VERSION 5.8 ;
BUSBITCHARS "[]" ;
DIVIDERCHAR "/" ;
UNITS
    DATABASE MICRONS 1000 ;
END UNITS

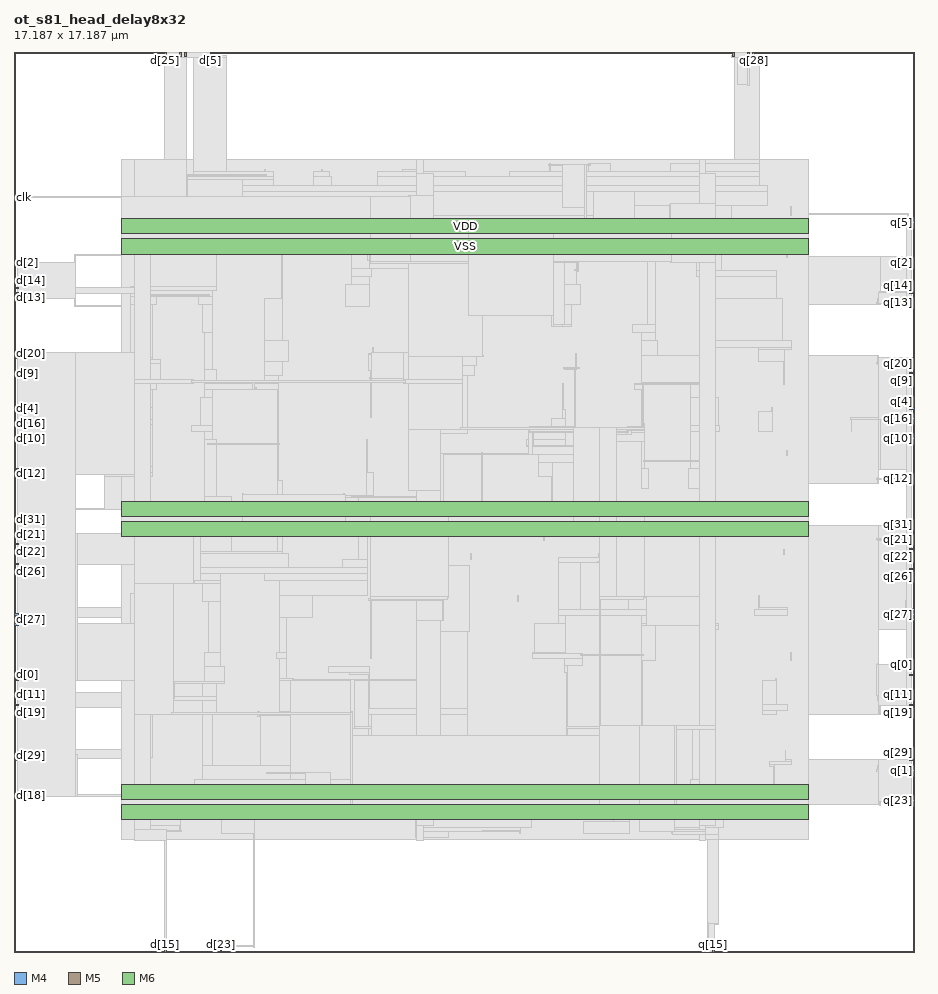
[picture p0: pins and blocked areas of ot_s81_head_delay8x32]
MACRO ot_s81_head_delay8x32
  FOREIGN ot_s81_head_delay8x32 0 0 ;
  CLASS BLOCK ;
  SIZE 17.187 BY 17.187 ;
  PIN clk
    DIRECTION INPUT ;
    USE SIGNAL ;
    PORT
      LAYER M4 ;
        RECT  0 14.4 0.084 14.424 ;
    END
  END clk
  PIN d[0]
    DIRECTION INPUT ;
    USE SIGNAL ;
    PORT
      LAYER M4 ;
        RECT  0 5.28 0.084 5.304 ;
    END
  END d[0]
  PIN d[10]
    DIRECTION INPUT ;
    USE SIGNAL ;
    PORT
      LAYER M4 ;
        RECT  0 9.792 0.084 9.816 ;
    END
  END d[10]
  PIN d[11]
    DIRECTION INPUT ;
    USE SIGNAL ;
    PORT
      LAYER M4 ;
        RECT  0 4.896 0.084 4.92 ;
    END
  END d[11]
  PIN d[12]
    DIRECTION INPUT ;
    USE SIGNAL ;
    PORT
      LAYER M4 ;
        RECT  0 9.12 0.084 9.144 ;
    END
  END d[12]
  PIN d[13]
    DIRECTION INPUT ;
    USE SIGNAL ;
    PORT
      LAYER M4 ;
        RECT  0 12.48 0.084 12.504 ;
    END
  END d[13]
  PIN d[14]
    DIRECTION INPUT ;
    USE SIGNAL ;
    PORT
      LAYER M4 ;
        RECT  0 12.672 0.084 12.696 ;
    END
  END d[14]
  PIN d[15]
    DIRECTION INPUT ;
    USE SIGNAL ;
    PORT
      LAYER M5 ;
        RECT  2.88 0 2.904 0.084 ;
    END
  END d[15]
  PIN d[16]
    DIRECTION INPUT ;
    USE SIGNAL ;
    PORT
      LAYER M4 ;
        RECT  0 10.08 0.084 10.104 ;
    END
  END d[16]
  PIN d[17]
    DIRECTION INPUT ;
    USE SIGNAL ;
    PORT
      LAYER M4 ;
        RECT  0 5.184 0.084 5.208 ;
    END
  END d[17]
  PIN d[18]
    DIRECTION INPUT ;
    USE SIGNAL ;
    PORT
      LAYER M4 ;
        RECT  0 2.976 0.084 3 ;
    END
  END d[18]
  PIN d[19]
    DIRECTION INPUT ;
    USE SIGNAL ;
    PORT
      LAYER M4 ;
        RECT  0 4.704 0.084 4.728 ;
    END
  END d[19]
  PIN d[1]
    DIRECTION INPUT ;
    USE SIGNAL ;
    PORT
      LAYER M4 ;
        RECT  0 3.648 0.084 3.672 ;
    END
  END d[1]
  PIN d[20]
    DIRECTION INPUT ;
    USE SIGNAL ;
    PORT
      LAYER M4 ;
        RECT  0 11.424 0.084 11.448 ;
    END
  END d[20]
  PIN d[21]
    DIRECTION INPUT ;
    USE SIGNAL ;
    PORT
      LAYER M4 ;
        RECT  0 7.968 0.084 7.992 ;
    END
  END d[21]
  PIN d[22]
    DIRECTION INPUT ;
    USE SIGNAL ;
    PORT
      LAYER M4 ;
        RECT  0 7.776 0.084 7.8 ;
    END
  END d[22]
  PIN d[23]
    DIRECTION INPUT ;
    USE SIGNAL ;
    PORT
      LAYER M5 ;
        RECT  3.936 0 3.96 0.084 ;
    END
  END d[23]
  PIN d[24]
    DIRECTION INPUT ;
    USE SIGNAL ;
    PORT
      LAYER M4 ;
        RECT  0 11.328 0.084 11.352 ;
    END
  END d[24]
  PIN d[25]
    DIRECTION INPUT ;
    USE SIGNAL ;
    PORT
      LAYER M5 ;
        RECT  2.88 17.103 2.904 17.187 ;
    END
  END d[25]
  PIN d[26]
    DIRECTION INPUT ;
    USE SIGNAL ;
    PORT
      LAYER M4 ;
        RECT  0 7.392 0.084 7.416 ;
    END
  END d[26]
  PIN d[27]
    DIRECTION INPUT ;
    USE SIGNAL ;
    PORT
      LAYER M4 ;
        RECT  0 6.336 0.084 6.36 ;
    END
  END d[27]
  PIN d[28]
    DIRECTION INPUT ;
    USE SIGNAL ;
    PORT
      LAYER M5 ;
        RECT  3.264 17.103 3.288 17.187 ;
    END
  END d[28]
  PIN d[29]
    DIRECTION INPUT ;
    USE SIGNAL ;
    PORT
      LAYER M4 ;
        RECT  0 3.744 0.084 3.768 ;
    END
  END d[29]
  PIN d[2]
    DIRECTION INPUT ;
    USE SIGNAL ;
    PORT
      LAYER M4 ;
        RECT  0 13.152 0.084 13.176 ;
    END
  END d[2]
  PIN d[30]
    DIRECTION INPUT ;
    USE SIGNAL ;
    PORT
      LAYER M5 ;
        RECT  3.168 17.103 3.192 17.187 ;
    END
  END d[30]
  PIN d[31]
    DIRECTION INPUT ;
    USE SIGNAL ;
    PORT
      LAYER M4 ;
        RECT  0 8.256 0.084 8.28 ;
    END
  END d[31]
  PIN d[3]
    DIRECTION INPUT ;
    USE SIGNAL ;
    PORT
      LAYER M4 ;
        RECT  0 6.432 0.084 6.456 ;
    END
  END d[3]
  PIN d[4]
    DIRECTION INPUT ;
    USE SIGNAL ;
    PORT
      LAYER M4 ;
        RECT  0 10.368 0.084 10.392 ;
    END
  END d[4]
  PIN d[5]
    DIRECTION INPUT ;
    USE SIGNAL ;
    PORT
      LAYER M5 ;
        RECT  3.744 17.103 3.768 17.187 ;
    END
  END d[5]
  PIN d[6]
    DIRECTION INPUT ;
    USE SIGNAL ;
    PORT
      LAYER M4 ;
        RECT  0 12.576 0.084 12.6 ;
    END
  END d[6]
  PIN d[7]
    DIRECTION INPUT ;
    USE SIGNAL ;
    PORT
      LAYER M4 ;
        RECT  0 9.216 0.084 9.24 ;
    END
  END d[7]
  PIN d[8]
    DIRECTION INPUT ;
    USE SIGNAL ;
    PORT
      LAYER M4 ;
        RECT  0 6.24 0.084 6.264 ;
    END
  END d[8]
  PIN d[9]
    DIRECTION INPUT ;
    USE SIGNAL ;
    PORT
      LAYER M4 ;
        RECT  0 11.04 0.084 11.064 ;
    END
  END d[9]
  PIN q[0]
    DIRECTION OUTPUT ;
    USE SIGNAL ;
    PORT
      LAYER M4 ;
        RECT  17.103 5.472 17.187 5.496 ;
    END
  END q[0]
  PIN q[10]
    DIRECTION OUTPUT ;
    USE SIGNAL ;
    PORT
      LAYER M4 ;
        RECT  17.103 9.792 17.187 9.816 ;
    END
  END q[10]
  PIN q[11]
    DIRECTION OUTPUT ;
    USE SIGNAL ;
    PORT
      LAYER M4 ;
        RECT  17.103 4.896 17.187 4.92 ;
    END
  END q[11]
  PIN q[12]
    DIRECTION OUTPUT ;
    USE SIGNAL ;
    PORT
      LAYER M4 ;
        RECT  17.103 9.024 17.187 9.048 ;
    END
  END q[12]
  PIN q[13]
    DIRECTION OUTPUT ;
    USE SIGNAL ;
    PORT
      LAYER M4 ;
        RECT  17.103 12.384 17.187 12.408 ;
    END
  END q[13]
  PIN q[14]
    DIRECTION OUTPUT ;
    USE SIGNAL ;
    PORT
      LAYER M4 ;
        RECT  17.103 12.576 17.187 12.6 ;
    END
  END q[14]
  PIN q[15]
    DIRECTION OUTPUT ;
    USE SIGNAL ;
    PORT
      LAYER M5 ;
        RECT  13.344 0 13.368 0.084 ;
    END
  END q[15]
  PIN q[16]
    DIRECTION OUTPUT ;
    USE SIGNAL ;
    PORT
      LAYER M4 ;
        RECT  17.103 10.176 17.187 10.2 ;
    END
  END q[16]
  PIN q[17]
    DIRECTION OUTPUT ;
    USE SIGNAL ;
    PORT
      LAYER M4 ;
        RECT  17.103 5.28 17.187 5.304 ;
    END
  END q[17]
  PIN q[18]
    DIRECTION OUTPUT ;
    USE SIGNAL ;
    PORT
      LAYER M5 ;
        RECT  13.248 0 13.272 0.084 ;
    END
  END q[18]
  PIN q[19]
    DIRECTION OUTPUT ;
    USE SIGNAL ;
    PORT
      LAYER M4 ;
        RECT  17.103 4.704 17.187 4.728 ;
    END
  END q[19]
  PIN q[1]
    DIRECTION OUTPUT ;
    USE SIGNAL ;
    PORT
      LAYER M4 ;
        RECT  17.103 3.456 17.187 3.48 ;
    END
  END q[1]
  PIN q[20]
    DIRECTION OUTPUT ;
    USE SIGNAL ;
    PORT
      LAYER M4 ;
        RECT  17.103 11.232 17.187 11.256 ;
    END
  END q[20]
  PIN q[21]
    DIRECTION OUTPUT ;
    USE SIGNAL ;
    PORT
      LAYER M4 ;
        RECT  17.103 7.872 17.187 7.896 ;
    END
  END q[21]
  PIN q[22]
    DIRECTION OUTPUT ;
    USE SIGNAL ;
    PORT
      LAYER M4 ;
        RECT  17.103 7.68 17.187 7.704 ;
    END
  END q[22]
  PIN q[23]
    DIRECTION OUTPUT ;
    USE SIGNAL ;
    PORT
      LAYER M4 ;
        RECT  17.103 2.88 17.187 2.904 ;
    END
  END q[23]
  PIN q[24]
    DIRECTION OUTPUT ;
    USE SIGNAL ;
    PORT
      LAYER M4 ;
        RECT  17.103 11.328 17.187 11.352 ;
    END
  END q[24]
  PIN q[25]
    DIRECTION OUTPUT ;
    USE SIGNAL ;
    PORT
      LAYER M5 ;
        RECT  13.728 17.103 13.752 17.187 ;
    END
  END q[25]
  PIN q[26]
    DIRECTION OUTPUT ;
    USE SIGNAL ;
    PORT
      LAYER M4 ;
        RECT  17.103 7.296 17.187 7.32 ;
    END
  END q[26]
  PIN q[27]
    DIRECTION OUTPUT ;
    USE SIGNAL ;
    PORT
      LAYER M4 ;
        RECT  17.103 6.432 17.187 6.456 ;
    END
  END q[27]
  PIN q[28]
    DIRECTION OUTPUT ;
    USE SIGNAL ;
    PORT
      LAYER M5 ;
        RECT  14.112 17.103 14.136 17.187 ;
    END
  END q[28]
  PIN q[29]
    DIRECTION OUTPUT ;
    USE SIGNAL ;
    PORT
      LAYER M4 ;
        RECT  17.103 3.648 17.187 3.672 ;
    END
  END q[29]
  PIN q[2]
    DIRECTION OUTPUT ;
    USE SIGNAL ;
    PORT
      LAYER M4 ;
        RECT  17.103 13.152 17.187 13.176 ;
    END
  END q[2]
  PIN q[30]
    DIRECTION OUTPUT ;
    USE SIGNAL ;
    PORT
      LAYER M5 ;
        RECT  14.016 17.103 14.04 17.187 ;
    END
  END q[30]
  PIN q[31]
    DIRECTION OUTPUT ;
    USE SIGNAL ;
    PORT
      LAYER M4 ;
        RECT  17.103 8.16 17.187 8.184 ;
    END
  END q[31]
  PIN q[3]
    DIRECTION OUTPUT ;
    USE SIGNAL ;
    PORT
      LAYER M4 ;
        RECT  17.103 6.528 17.187 6.552 ;
    END
  END q[3]
  PIN q[4]
    DIRECTION OUTPUT ;
    USE SIGNAL ;
    PORT
      LAYER M4 ;
        RECT  17.103 10.368 17.187 10.392 ;
    END
  END q[4]
  PIN q[5]
    DIRECTION OUTPUT ;
    USE SIGNAL ;
    PORT
      LAYER M4 ;
        RECT  17.103 13.92 17.187 13.944 ;
    END
  END q[5]
  PIN q[6]
    DIRECTION OUTPUT ;
    USE SIGNAL ;
    PORT
      LAYER M4 ;
        RECT  17.103 12.48 17.187 12.504 ;
    END
  END q[6]
  PIN q[7]
    DIRECTION OUTPUT ;
    USE SIGNAL ;
    PORT
      LAYER M4 ;
        RECT  17.103 9.12 17.187 9.144 ;
    END
  END q[7]
  PIN q[8]
    DIRECTION OUTPUT ;
    USE SIGNAL ;
    PORT
      LAYER M4 ;
        RECT  17.103 6.336 17.187 6.36 ;
    END
  END q[8]
  PIN q[9]
    DIRECTION OUTPUT ;
    USE SIGNAL ;
    PORT
      LAYER M4 ;
        RECT  17.103 11.04 17.187 11.064 ;
    END
  END q[9]
  PIN VDD
    DIRECTION INOUT ;
    USE POWER ;
    PORT
      LAYER M6 ;
        RECT  2.052 13.713 15.174 14.001 ;
        RECT  2.052 8.313 15.174 8.601 ;
        RECT  2.052 2.913 15.174 3.201 ;
    END
  END VDD
  PIN VSS
    DIRECTION INOUT ;
    USE GROUND ;
    PORT
      LAYER M6 ;
        RECT  2.052 13.329 15.174 13.617 ;
        RECT  2.052 7.929 15.174 8.217 ;
        RECT  2.052 2.529 15.174 2.817 ;
    END
  END VSS
  OBS
    LAYER RVTN ;
     RECT  2.052 2.16 15.174 2.295 ;
     RECT  2.052 2.565 15.174 2.835 ;
     RECT  2.052 3.105 15.174 3.375 ;
     RECT  2.052 3.645 15.174 3.915 ;
     RECT  2.052 4.185 15.174 4.455 ;
     RECT  2.052 4.725 15.174 4.995 ;
     RECT  2.052 5.265 15.174 5.535 ;
     RECT  2.052 5.805 15.174 6.075 ;
     RECT  2.052 6.345 15.174 6.615 ;
     RECT  2.052 6.885 15.174 7.155 ;
     RECT  2.052 7.425 15.174 7.695 ;
     RECT  2.052 7.965 15.174 8.235 ;
     RECT  2.052 8.505 15.174 8.775 ;
     RECT  2.052 9.045 15.174 9.315 ;
     RECT  2.052 9.585 15.174 9.855 ;
     RECT  2.052 10.125 15.174 10.395 ;
     RECT  2.052 10.665 15.174 10.935 ;
     RECT  2.052 11.205 15.174 11.475 ;
     RECT  2.052 11.745 15.174 12.015 ;
     RECT  2.052 12.285 15.174 12.555 ;
     RECT  2.052 12.825 15.174 13.095 ;
     RECT  2.052 13.365 15.174 13.635 ;
     RECT  2.052 13.905 15.174 14.175 ;
     RECT  2.052 14.445 15.174 14.715 ;
     RECT  2.052 14.985 15.174 15.12 ;
    LAYER RVTP ;
     RECT  2.052 2.295 15.174 2.565 ;
     RECT  2.052 2.835 15.174 3.105 ;
     RECT  2.052 3.375 15.174 3.645 ;
     RECT  2.052 3.915 15.174 4.185 ;
     RECT  2.052 4.455 15.174 4.725 ;
     RECT  2.052 4.995 15.174 5.265 ;
     RECT  2.052 5.535 15.174 5.805 ;
     RECT  2.052 6.075 15.174 6.345 ;
     RECT  2.052 6.615 15.174 6.885 ;
     RECT  2.052 7.155 15.174 7.425 ;
     RECT  2.052 7.695 15.174 7.965 ;
     RECT  2.052 8.235 15.174 8.505 ;
     RECT  2.052 8.775 15.174 9.045 ;
     RECT  2.052 9.315 15.174 9.585 ;
     RECT  2.052 9.855 15.174 10.125 ;
     RECT  2.052 10.395 15.174 10.665 ;
     RECT  2.052 10.935 15.174 11.205 ;
     RECT  2.052 11.475 15.174 11.745 ;
     RECT  2.052 12.015 15.174 12.285 ;
     RECT  2.052 12.555 15.174 12.825 ;
     RECT  2.052 13.095 15.174 13.365 ;
     RECT  2.052 13.635 15.174 13.905 ;
     RECT  2.052 14.175 15.174 14.445 ;
     RECT  2.052 14.715 15.174 14.985 ;
    LAYER M1 ;
     RECT  2.052 2.151 15.174 15.129 ;
    LAYER M2 ;
     RECT  1.147 3.852 1.183 3.87 ;
     RECT  1.147 6.552 1.183 6.57 ;
     RECT  1.147 8.442 1.723 8.46 ;
     RECT  1.147 9.792 1.723 9.81 ;
     RECT  1.183 3.69 2.052 3.87 ;
     RECT  1.147 4.662 2.052 4.95 ;
     RECT  1.183 6.39 2.052 6.57 ;
     RECT  1.723 8.442 2.052 9.81 ;
     RECT  1.147 12.33 2.052 12.348 ;
     RECT  1.147 13.302 2.052 13.32 ;
     RECT  2.052 2.151 15.174 15.129 ;
     RECT  15.174 2.808 16.511 3.672 ;
     RECT  15.174 4.536 16.511 8.154 ;
     RECT  15.174 8.946 16.511 11.394 ;
     RECT  16.511 2.808 16.547 2.826 ;
     RECT  16.511 3.654 16.547 3.672 ;
     RECT  16.511 4.536 16.547 5.184 ;
     RECT  16.511 9.216 16.547 11.304 ;
     RECT  15.174 12.366 16.547 13.284 ;
     RECT  16.511 6.156 17.087 8.154 ;
     RECT  16.547 9.216 17.087 10.314 ;
     RECT  16.547 12.726 17.087 13.284 ;
     RECT  15.174 14.076 17.087 14.094 ;
    LAYER M3 ;
     RECT  13.248 0.091 13.266 0.523 ;
     RECT  13.248 0.523 13.446 2.143 ;
     RECT  7.707 2.143 7.797 2.191 ;
     RECT  13.107 2.143 13.446 2.251 ;
     RECT  4.572 0.091 4.59 2.263 ;
     RECT  7.668 2.191 8.298 2.299 ;
     RECT  9.648 2.263 9.666 2.299 ;
     RECT  7.668 2.299 9.666 2.371 ;
     RECT  12.6 2.251 13.446 2.371 ;
     RECT  2.307 2.143 2.397 2.413 ;
     RECT  3.168 2.299 3.186 2.413 ;
     RECT  10.872 2.263 11.754 2.489 ;
     RECT  3.96 2.263 4.59 2.605 ;
     RECT  7.668 2.371 9.882 2.605 ;
     RECT  3.96 2.605 5.31 2.618 ;
     RECT  2.307 2.413 3.186 2.641 ;
     RECT  3.96 2.618 5.598 2.641 ;
     RECT  6.408 2.605 6.498 2.641 ;
     RECT  11.448 2.489 11.754 2.641 ;
     RECT  12.6 2.371 13.554 2.641 ;
     RECT  7.488 2.605 9.882 2.759 ;
     RECT  2.307 2.641 5.598 2.795 ;
     RECT  14.688 2.731 14.706 2.795 ;
     RECT  16.524 2.803 16.542 2.909 ;
     RECT  3.312 2.795 5.598 2.911 ;
     RECT  6.408 2.641 6.678 2.911 ;
     RECT  7.488 2.759 9.378 2.911 ;
     RECT  10.656 2.641 10.674 2.911 ;
     RECT  11.448 2.641 13.554 2.911 ;
     RECT  11.448 2.911 13.662 2.912 ;
     RECT  3.312 2.911 9.378 3.029 ;
     RECT  10.188 2.911 10.674 3.029 ;
     RECT  11.484 2.912 13.662 3.029 ;
     RECT  3.456 3.029 8.982 3.173 ;
     RECT  3.456 3.173 8.946 3.299 ;
     RECT  11.484 3.029 12.042 3.299 ;
     RECT  12.924 3.029 13.389 3.299 ;
     RECT  6.012 3.299 6.03 3.437 ;
     RECT  7.707 3.299 8.946 3.479 ;
     RECT  14.508 2.911 14.526 3.541 ;
     RECT  3.6 3.299 5.274 3.569 ;
     RECT  16.488 3.451 16.506 3.569 ;
     RECT  14.436 3.541 14.526 3.577 ;
     RECT  14.436 3.577 14.85 3.641 ;
     RECT  14.724 3.641 14.85 3.677 ;
     RECT  16.524 3.643 16.542 3.683 ;
     RECT  1.152 3.643 1.17 3.685 ;
     RECT  2.307 2.795 2.589 3.721 ;
     RECT  1.152 3.685 1.206 3.773 ;
     RECT  11.556 3.299 12.042 3.839 ;
     RECT  14.724 3.677 14.742 3.839 ;
     RECT  1.152 3.773 1.17 3.875 ;
     RECT  7.707 3.479 8.802 4.109 ;
     RECT  10.224 3.029 10.566 4.109 ;
     RECT  6.768 3.299 6.822 4.261 ;
     RECT  10.548 4.109 10.566 4.261 ;
     RECT  11.988 3.839 12.042 4.261 ;
     RECT  12.96 3.299 13.389 4.261 ;
     RECT  6.444 4.261 6.822 4.301 ;
     RECT  10.548 4.261 11.214 4.301 ;
     RECT  11.988 4.261 13.389 4.301 ;
     RECT  4.716 3.569 5.274 4.507 ;
     RECT  3.6 3.569 3.798 4.531 ;
     RECT  6.768 4.301 6.822 4.531 ;
     RECT  7.707 4.109 8.658 4.531 ;
     RECT  4.68 4.507 5.274 4.559 ;
     RECT  14.292 4.531 14.562 4.621 ;
     RECT  6.768 4.531 8.658 4.649 ;
     RECT  14.292 4.621 14.778 4.721 ;
     RECT  2.307 3.721 2.646 4.801 ;
     RECT  3.6 4.531 3.87 4.801 ;
     RECT  16.524 4.531 16.542 4.801 ;
     RECT  2.307 4.801 3.87 4.877 ;
     RECT  1.152 4.657 1.17 4.955 ;
     RECT  3.6 4.877 3.87 5.131 ;
     RECT  3.6 5.131 4.014 5.165 ;
     RECT  5.076 4.559 5.274 5.179 ;
     RECT  14.292 4.721 14.562 5.189 ;
     RECT  5.076 5.179 5.346 5.225 ;
     RECT  14.544 5.189 14.562 5.225 ;
     RECT  2.307 4.877 2.79 5.275 ;
     RECT  6.768 4.649 6.786 5.305 ;
     RECT  16.488 4.801 16.542 5.309 ;
     RECT  6.408 5.305 6.786 5.341 ;
     RECT  10.548 4.301 10.566 5.341 ;
     RECT  3.636 5.165 4.014 5.459 ;
     RECT  6.012 5.341 6.786 5.459 ;
     RECT  10.512 5.341 10.566 5.467 ;
     RECT  2.268 5.275 2.79 5.495 ;
     RECT  16.488 5.309 16.506 5.501 ;
     RECT  11.988 4.301 12.006 5.575 ;
     RECT  5.076 5.225 5.202 5.611 ;
     RECT  10.512 5.467 10.854 5.611 ;
     RECT  9.9 5.611 10.854 5.693 ;
     RECT  3.636 5.459 3.942 5.729 ;
     RECT  5.004 5.611 5.202 5.729 ;
     RECT  9.9 5.693 10.53 5.729 ;
     RECT  14.832 5.575 14.85 5.729 ;
     RECT  7.707 4.649 8.658 6.115 ;
     RECT  2.307 5.495 2.79 6.151 ;
     RECT  13.107 4.301 13.389 6.151 ;
     RECT  2.307 6.151 2.862 6.235 ;
     RECT  11.988 5.575 12.258 6.235 ;
     RECT  13.104 6.151 13.446 6.235 ;
     RECT  9.936 5.729 10.53 6.269 ;
     RECT  11.988 6.235 13.446 6.269 ;
     RECT  1.152 6.331 1.17 6.385 ;
     RECT  5.076 5.729 5.202 6.385 ;
     RECT  10.404 6.269 10.53 6.421 ;
     RECT  11.988 6.269 13.389 6.421 ;
     RECT  1.152 6.385 1.206 6.461 ;
     RECT  17.064 6.151 17.082 6.523 ;
     RECT  10.404 6.421 13.389 6.539 ;
     RECT  14.148 6.421 14.778 6.539 ;
     RECT  1.152 6.461 1.17 6.575 ;
     RECT  14.22 6.539 14.778 6.575 ;
     RECT  3.708 5.729 3.942 6.691 ;
     RECT  17.028 6.523 17.082 6.719 ;
     RECT  6.804 5.611 6.822 6.749 ;
     RECT  11.736 6.539 13.389 6.797 ;
     RECT  9.612 6.691 9.63 6.809 ;
     RECT  14.22 6.575 14.238 6.809 ;
     RECT  5.076 6.385 5.706 6.817 ;
     RECT  2.232 6.235 2.862 6.845 ;
     RECT  2.304 6.845 2.862 7.045 ;
     RECT  3.6 6.691 3.942 7.045 ;
     RECT  2.304 7.045 3.942 7.085 ;
     RECT  5.076 6.817 6.75 7.087 ;
     RECT  3.564 7.085 3.942 7.231 ;
     RECT  4.788 7.087 6.75 7.231 ;
     RECT  2.304 7.085 2.826 7.259 ;
     RECT  3.564 7.231 6.75 7.349 ;
     RECT  7.707 6.115 8.694 7.385 ;
     RECT  10.404 6.539 10.818 7.435 ;
     RECT  11.736 6.797 11.826 7.435 ;
     RECT  6.264 7.349 6.75 7.493 ;
     RECT  10.404 7.435 11.826 7.529 ;
     RECT  3.564 7.349 5.238 7.619 ;
     RECT  8.712 7.501 8.73 7.619 ;
     RECT  11.16 7.529 11.826 7.619 ;
     RECT  3.564 7.619 5.13 7.655 ;
     RECT  14.688 7.591 14.706 7.691 ;
     RECT  17.064 6.719 17.082 7.861 ;
     RECT  16.488 7.861 17.082 7.901 ;
     RECT  2.304 7.259 2.646 7.963 ;
     RECT  13.107 6.797 13.389 7.969 ;
     RECT  10.116 7.861 10.134 8.159 ;
     RECT  17.064 7.901 17.082 8.189 ;
     RECT  2.268 7.963 2.646 8.195 ;
     RECT  6.588 7.493 6.75 8.311 ;
     RECT  13.107 7.969 13.446 8.311 ;
     RECT  3.564 7.655 4.158 8.401 ;
     RECT  5.04 7.655 5.13 8.401 ;
     RECT  3.564 8.401 5.13 8.429 ;
     RECT  13.107 8.311 13.59 8.429 ;
     RECT  1.152 8.251 1.17 8.465 ;
     RECT  11.808 7.619 11.826 8.465 ;
     RECT  3.636 8.429 5.13 8.477 ;
     RECT  7.707 7.385 7.989 8.539 ;
     RECT  6.588 8.311 6.966 8.545 ;
     RECT  7.707 8.539 8.046 8.545 ;
     RECT  10.26 8.275 10.458 8.573 ;
     RECT  6.588 8.545 8.046 8.671 ;
     RECT  3.636 8.477 4.158 8.699 ;
     RECT  6.408 8.671 8.046 8.699 ;
     RECT  6.408 8.699 6.858 8.717 ;
     RECT  13.107 8.429 13.389 8.851 ;
     RECT  5.04 8.477 5.13 9.005 ;
     RECT  7.707 8.699 8.046 9.005 ;
     RECT  16.488 8.941 16.506 9.053 ;
     RECT  2.307 8.195 2.589 9.085 ;
     RECT  10.26 8.573 10.278 9.085 ;
     RECT  1.728 9.085 2.646 9.149 ;
     RECT  6.732 8.717 6.858 9.149 ;
     RECT  11.988 8.851 12.114 9.239 ;
     RECT  12.888 8.851 13.389 9.239 ;
     RECT  2.196 9.149 2.646 9.275 ;
     RECT  10.008 9.085 10.278 9.355 ;
     RECT  10.008 9.355 10.746 9.499 ;
     RECT  8.928 8.005 8.946 9.533 ;
     RECT  14.76 9.481 14.778 9.581 ;
     RECT  9.864 9.499 10.746 9.661 ;
     RECT  9.792 9.661 10.746 9.677 ;
     RECT  11.988 9.239 12.042 9.751 ;
     RECT  3.636 8.699 3.87 9.779 ;
     RECT  6.732 9.149 6.75 9.779 ;
     RECT  9.792 9.677 10.53 9.779 ;
     RECT  1.152 9.787 1.17 9.824 ;
     RECT  7.707 9.005 7.989 9.895 ;
     RECT  11.484 9.751 12.042 9.923 ;
     RECT  3.636 9.779 3.798 9.931 ;
     RECT  12.924 9.239 13.389 9.931 ;
     RECT  9.864 9.779 10.53 9.965 ;
     RECT  11.736 9.923 12.042 9.965 ;
     RECT  3.384 9.931 3.798 10.049 ;
     RECT  12.924 9.931 13.482 10.049 ;
     RECT  2.307 9.275 2.646 10.075 ;
     RECT  11.988 9.965 12.042 10.085 ;
     RECT  2.232 10.075 2.646 10.165 ;
     RECT  10.26 9.965 10.53 10.193 ;
     RECT  15.984 9.931 16.002 10.205 ;
     RECT  14.22 9.931 14.49 10.319 ;
     RECT  10.476 10.193 10.53 10.355 ;
     RECT  14.472 10.319 14.49 10.391 ;
     RECT  2.196 10.165 2.646 10.397 ;
     RECT  17.064 9.115 17.082 10.397 ;
     RECT  3.564 10.049 3.798 10.589 ;
     RECT  12.924 10.049 13.446 10.589 ;
     RECT  2.232 10.397 2.646 10.741 ;
     RECT  3.636 10.589 3.798 10.741 ;
     RECT  5.04 9.005 5.058 10.741 ;
     RECT  11.988 10.085 12.006 10.741 ;
     RECT  11.844 10.741 12.006 10.843 ;
     RECT  12.924 10.589 13.389 10.843 ;
     RECT  3.636 10.741 5.058 10.859 ;
     RECT  10.476 10.355 10.494 10.859 ;
     RECT  11.844 10.843 13.389 10.859 ;
     RECT  2.232 10.741 2.718 10.891 ;
     RECT  2.232 10.891 2.898 10.931 ;
     RECT  4.788 10.859 5.058 11.011 ;
     RECT  7.707 9.895 8.658 11.011 ;
     RECT  6.804 10.201 6.822 11.101 ;
     RECT  3.636 10.859 3.87 11.129 ;
     RECT  10.512 11.131 10.746 11.171 ;
     RECT  7.707 11.011 8.802 11.209 ;
     RECT  16.524 11.011 16.542 11.227 ;
     RECT  2.232 10.931 2.79 11.245 ;
     RECT  4.788 11.011 5.13 11.281 ;
     RECT  14.688 10.831 14.706 11.281 ;
     RECT  2.196 11.245 2.79 11.309 ;
     RECT  2.196 11.309 2.646 11.357 ;
     RECT  16.488 11.227 16.542 11.357 ;
     RECT  11.988 10.859 13.389 11.399 ;
     RECT  16.488 11.357 16.506 11.399 ;
     RECT  6.768 11.101 6.822 11.407 ;
     RECT  6.768 11.407 6.93 11.435 ;
     RECT  10.728 11.171 10.746 11.435 ;
     RECT  6.84 11.435 6.93 11.453 ;
     RECT  14.22 11.281 14.706 11.515 ;
     RECT  6.84 11.453 6.858 11.543 ;
     RECT  13.107 11.399 13.389 11.551 ;
     RECT  14.22 11.515 14.85 11.551 ;
     RECT  4.788 11.281 5.238 11.669 ;
     RECT  11.988 11.399 12.294 11.669 ;
     RECT  13.107 11.551 14.85 11.669 ;
     RECT  3.636 11.129 3.798 11.821 ;
     RECT  11.988 11.669 12.258 11.821 ;
     RECT  11.808 11.821 12.258 11.975 ;
     RECT  10.44 11.947 10.638 11.984 ;
     RECT  7.707 11.209 8.838 12.325 ;
     RECT  2.232 11.357 2.646 12.361 ;
     RECT  3.6 11.821 3.798 12.361 ;
     RECT  10.512 11.984 10.638 12.361 ;
     RECT  16.524 12.361 16.542 12.379 ;
     RECT  16.488 12.379 16.542 12.475 ;
     RECT  4.788 11.669 5.13 12.479 ;
     RECT  7.707 12.325 8.91 12.479 ;
     RECT  13.107 11.669 14.67 12.479 ;
     RECT  16.488 12.475 17.082 12.479 ;
     RECT  2.232 12.361 2.718 12.523 ;
     RECT  3.528 12.361 3.798 12.523 ;
     RECT  16.524 12.479 17.082 12.605 ;
     RECT  2.232 12.523 3.798 12.631 ;
     RECT  2.232 12.631 3.87 12.701 ;
     RECT  6.336 12.325 6.786 12.749 ;
     RECT  10.512 12.361 10.818 12.749 ;
     RECT  6.444 12.749 6.786 12.901 ;
     RECT  13.107 12.479 14.562 12.901 ;
     RECT  13.032 12.901 14.562 13.019 ;
     RECT  6.444 12.901 6.822 13.051 ;
     RECT  10.512 12.749 10.746 13.171 ;
     RECT  1.152 12.325 1.17 13.325 ;
     RECT  7.707 12.479 8.694 13.333 ;
     RECT  14.76 13.261 14.778 13.361 ;
     RECT  7.707 13.333 8.946 13.405 ;
     RECT  2.307 12.701 3.87 13.441 ;
     RECT  5.112 12.479 5.13 13.441 ;
     RECT  12.096 11.975 12.258 13.441 ;
     RECT  13.032 13.019 13.518 13.441 ;
     RECT  2.307 13.441 5.13 13.559 ;
     RECT  6.444 13.051 6.966 13.639 ;
     RECT  2.307 13.559 3.438 13.661 ;
     RECT  6.264 13.639 6.966 13.711 ;
     RECT  9.936 13.171 10.746 13.711 ;
     RECT  6.012 13.711 6.966 13.819 ;
     RECT  5.868 13.819 6.966 13.963 ;
     RECT  7.707 13.405 9.126 13.963 ;
     RECT  12.096 13.441 13.518 13.963 ;
     RECT  5.868 13.963 9.126 13.981 ;
     RECT  9.936 13.711 10.998 13.981 ;
     RECT  11.988 13.963 13.518 13.981 ;
     RECT  4.356 13.559 5.13 14.071 ;
     RECT  5.868 13.981 11.07 14.071 ;
     RECT  17.064 12.605 17.082 14.099 ;
     RECT  14.832 14.071 14.85 14.243 ;
     RECT  11.844 13.981 13.698 14.251 ;
     RECT  4.356 14.071 11.07 14.521 ;
     RECT  11.844 14.251 14.382 14.521 ;
     RECT  4.356 14.521 14.382 14.639 ;
     RECT  2.307 13.661 3.294 14.755 ;
     RECT  4.356 14.639 4.95 14.755 ;
     RECT  2.307 14.755 4.95 14.813 ;
     RECT  5.724 14.639 6.066 14.819 ;
     RECT  6.948 14.639 14.238 14.819 ;
     RECT  2.307 14.813 2.589 14.867 ;
     RECT  3.42 14.813 4.95 14.909 ;
     RECT  5.724 14.819 6.03 14.909 ;
     RECT  6.948 14.819 8.622 14.909 ;
     RECT  9.468 14.819 14.238 14.909 ;
     RECT  4.788 14.909 4.806 14.945 ;
     RECT  5.868 14.909 5.886 14.945 ;
     RECT  7.416 14.909 7.797 14.945 ;
     RECT  10.224 14.909 10.242 15.053 ;
     RECT  10.98 14.909 11.394 15.053 ;
     RECT  12.528 14.909 14.238 15.053 ;
     RECT  10.98 15.053 10.998 15.059 ;
     RECT  2.307 14.867 2.397 15.137 ;
     RECT  7.707 14.945 7.797 15.137 ;
     RECT  13.107 15.053 14.238 15.137 ;
     RECT  3.42 14.909 4.05 17.117 ;
     RECT  13.752 15.137 14.238 17.117 ;
    LAYER M4 ;
     RECT  0.06 14.4 0.131 14.424 ;
     RECT  0.06 2.976 1.181 11.448 ;
     RECT  0.06 12.48 1.181 13.176 ;
     RECT  1.181 2.976 1.217 3.768 ;
     RECT  1.181 5.184 1.217 7.992 ;
     RECT  1.181 12.576 2.293 12.696 ;
     RECT  1.217 2.976 2.3 3 ;
     RECT  1.217 5.184 2.3 6.264 ;
     RECT  1.217 7.392 2.3 7.992 ;
     RECT  1.181 9.12 2.3 11.448 ;
     RECT  2.293 12.528 2.3 12.696 ;
     RECT  2.3 2.148 2.404 15.132 ;
     RECT  2.404 2.304 2.596 14.862 ;
     RECT  2.596 4.848 2.657 5.208 ;
     RECT  2.657 4.848 3.059 5.16 ;
     RECT  2.596 2.304 3.197 2.328 ;
     RECT  2.596 13.632 3.305 14.856 ;
     RECT  2.596 7.056 3.443 7.08 ;
     RECT  2.596 10.896 3.443 10.92 ;
     RECT  3.305 13.632 3.449 13.656 ;
     RECT  2.596 12.528 3.737 12.552 ;
     RECT  2.596 8.352 3.989 8.472 ;
     RECT  3.059 5.136 4.025 5.16 ;
     RECT  3.157 17.088 4.061 17.112 ;
     RECT  3.989 8.448 4.403 8.472 ;
     RECT  3.925 0.096 4.601 0.12 ;
     RECT  4.549 10.752 4.637 10.776 ;
     RECT  4.645 4.512 4.732 4.536 ;
     RECT  4.561 13.68 4.741 13.704 ;
     RECT  3.305 14.832 4.817 14.856 ;
     RECT  3.697 9.696 5.069 9.72 ;
     RECT  5.065 4.56 5.285 4.584 ;
     RECT  4.813 3.408 5.569 3.432 ;
     RECT  4.741 13.68 6.037 13.848 ;
     RECT  5.569 2.64 6.041 3.432 ;
     RECT  5.317 5.184 6.421 5.208 ;
     RECT  6.277 8.688 6.437 8.712 ;
     RECT  6.421 4.272 6.508 5.208 ;
     RECT  6.037 13.68 6.757 13.992 ;
     RECT  6.757 13.2 6.793 13.992 ;
     RECT  6.793 10.944 6.829 10.968 ;
     RECT  6.829 10.944 7.429 11.448 ;
     RECT  6.764 6.72 7.573 6.744 ;
     RECT  6.041 2.64 7.7 2.664 ;
     RECT  6.508 5.184 7.7 5.208 ;
     RECT  7.573 6.72 7.7 6.936 ;
     RECT  7.525 8.832 7.7 8.856 ;
     RECT  7.429 10.896 7.7 11.448 ;
     RECT  6.793 13.056 7.7 13.992 ;
     RECT  7.7 2.148 7.804 15.132 ;
     RECT  7.804 2.418 7.996 14.862 ;
     RECT  7.996 10.944 8.021 12.216 ;
     RECT  7.996 6.24 8.147 6.792 ;
     RECT  8.147 6.336 8.195 6.792 ;
     RECT  7.996 8.544 8.195 9.528 ;
     RECT  8.195 6.768 8.291 6.792 ;
     RECT  8.021 11.376 8.723 12.216 ;
     RECT  7.996 3.408 8.771 3.432 ;
     RECT  8.723 11.376 8.963 11.4 ;
     RECT  7.996 13.488 8.963 13.512 ;
     RECT  8.953 2.304 9.677 2.328 ;
     RECT  8.195 9.504 9.829 9.528 ;
     RECT  9.829 9.504 9.893 9.96 ;
     RECT  9.893 9.648 9.916 9.96 ;
     RECT  10.213 15.024 10.465 15.048 ;
     RECT  10.261 11.952 10.469 11.976 ;
     RECT  9.916 9.648 10.78 9.672 ;
     RECT  10.7 13.008 10.787 13.032 ;
     RECT  10.501 11.136 10.8 11.16 ;
     RECT  10.465 14.208 10.897 15.048 ;
     RECT  10.897 13.968 10.937 15.048 ;
     RECT  10.937 15.024 11.009 15.048 ;
     RECT  10.465 3.6 11.173 3.624 ;
     RECT  11.149 7.44 11.233 7.464 ;
     RECT  11.173 3.6 11.26 4.296 ;
     RECT  11.26 3.6 11.437 3.624 ;
     RECT  11.437 2.88 11.621 3.624 ;
     RECT  11.461 9.888 11.701 9.912 ;
     RECT  11.701 9.888 11.788 9.96 ;
     RECT  11.621 2.88 11.987 3.432 ;
     RECT  10.825 5.664 12.017 5.688 ;
     RECT  11.987 3.408 12.053 3.432 ;
     RECT  11.989 6.768 12.085 6.792 ;
     RECT  10.937 13.968 12.517 13.992 ;
     RECT  12.517 13.968 12.553 14.28 ;
     RECT  12.565 2.256 13.1 2.28 ;
     RECT  12.613 4.272 13.1 4.296 ;
     RECT  12.085 6.24 13.1 6.792 ;
     RECT  12.013 9.36 13.1 9.384 ;
     RECT  11.989 10.848 13.1 10.872 ;
     RECT  12.553 13.584 13.1 14.28 ;
     RECT  13.1 2.148 13.204 15.132 ;
     RECT  13.237 0.096 13.379 0.552 ;
     RECT  13.204 2.418 13.396 14.862 ;
     RECT  13.379 0.528 13.457 0.552 ;
     RECT  13.697 17.088 13.813 17.112 ;
     RECT  13.813 16.56 14.051 17.112 ;
     RECT  14.051 17.088 14.249 17.112 ;
     RECT  16.477 3.456 16.513 3.48 ;
     RECT  16.477 4.896 16.513 5.496 ;
     RECT  15.973 10.176 16.513 10.2 ;
     RECT  16.477 11.232 16.513 11.256 ;
     RECT  16.477 12.384 16.513 12.408 ;
     RECT  16.513 4.704 17.053 5.496 ;
     RECT  17.017 6.528 17.053 6.552 ;
     RECT  16.477 7.872 17.053 7.896 ;
     RECT  16.477 9.024 17.053 9.048 ;
     RECT  16.513 10.176 17.053 11.352 ;
     RECT  16.513 12.384 17.053 12.6 ;
     RECT  16.513 2.88 17.148 3.672 ;
     RECT  17.053 4.704 17.148 11.352 ;
     RECT  17.053 12.384 17.148 13.944 ;
    LAYER M5 ;
     RECT  3.936 0.016 3.96 0.131 ;
     RECT  13.248 0.016 13.368 0.131 ;
     RECT  13.248 0.131 13.272 0.563 ;
     RECT  2.88 0.016 2.904 2.137 ;
     RECT  13.092 2.137 13.212 2.245 ;
     RECT  12.576 2.245 13.212 2.293 ;
     RECT  2.292 2.137 2.904 2.339 ;
     RECT  11.952 2.293 13.212 2.347 ;
     RECT  7.692 2.137 7.812 2.407 ;
     RECT  13.092 2.347 13.212 2.407 ;
     RECT  11.952 2.347 11.976 2.915 ;
     RECT  7.692 2.407 8.004 3.397 ;
     RECT  7.692 3.397 8.76 4.139 ;
     RECT  13.092 2.407 13.404 4.243 ;
     RECT  12.624 4.243 13.404 4.331 ;
     RECT  2.292 2.339 2.604 4.533 ;
     RECT  4.656 4.501 4.68 4.587 ;
     RECT  6.432 4.085 6.456 4.587 ;
     RECT  7.692 4.139 8.136 6.325 ;
     RECT  7.692 6.325 8.184 6.709 ;
     RECT  6.816 6.709 8.184 6.739 ;
     RECT  11.184 4.085 11.208 6.739 ;
     RECT  6.816 6.739 8.28 6.827 ;
     RECT  11.184 6.739 12.024 6.827 ;
     RECT  7.584 6.827 8.184 6.947 ;
     RECT  2.292 4.533 3.048 7.045 ;
     RECT  11.184 6.827 11.208 7.475 ;
     RECT  2.292 7.045 3.432 8.437 ;
     RECT  2.292 8.437 4.392 8.483 ;
     RECT  7.692 6.947 8.184 8.579 ;
     RECT  4.368 8.483 4.392 8.747 ;
     RECT  6.288 8.677 6.312 8.761 ;
     RECT  7.692 8.579 8.136 8.821 ;
     RECT  10.704 9.637 10.728 9.845 ;
     RECT  10.704 9.845 11.496 9.925 ;
     RECT  9.84 9.925 11.736 9.933 ;
     RECT  7.536 8.821 8.136 9.973 ;
     RECT  11.712 9.933 11.736 9.973 ;
     RECT  9.84 9.933 10.728 10.027 ;
     RECT  11.712 9.973 12.024 10.027 ;
     RECT  2.292 8.483 2.604 10.847 ;
     RECT  7.536 9.973 8.568 10.847 ;
     RECT  12 10.027 12.024 10.883 ;
     RECT  4.56 10.741 4.584 10.923 ;
     RECT  2.292 10.847 3.432 10.931 ;
     RECT  7.44 10.847 8.568 10.931 ;
     RECT  10.704 10.027 10.728 11.171 ;
     RECT  7.536 10.931 8.568 11.365 ;
     RECT  10.272 11.941 10.296 12.203 ;
     RECT  7.536 11.365 8.952 13.151 ;
     RECT  13.092 4.331 13.404 13.173 ;
     RECT  10.752 12.997 10.776 13.227 ;
     RECT  6.816 13.151 8.952 13.235 ;
     RECT  7.536 13.235 8.952 13.523 ;
     RECT  2.292 10.931 2.604 13.621 ;
     RECT  2.292 13.621 2.904 14.197 ;
     RECT  12.528 13.173 13.404 14.291 ;
     RECT  0.096 14.355 0.12 14.443 ;
     RECT  7.536 13.523 8.004 14.443 ;
     RECT  7.692 14.443 8.004 14.873 ;
     RECT  13.092 14.291 13.404 14.873 ;
     RECT  2.292 14.197 3.288 15.143 ;
     RECT  7.692 14.873 7.812 15.143 ;
     RECT  13.092 14.873 13.212 15.143 ;
     RECT  2.88 15.143 3.288 17.077 ;
     RECT  14.016 16.549 14.04 17.077 ;
     RECT  2.88 17.077 3.768 17.168 ;
     RECT  13.728 17.077 14.136 17.168 ;
    LAYER M6 ;
     RECT  0.085 14.4 2.052 14.432 ;
     RECT  2.052 7.929 4.357 8.601 ;
     RECT  4.357 7.929 6.323 8.736 ;
     RECT  2.052 2.529 6.421 3.201 ;
     RECT  3.013 4.544 6.421 4.576 ;
     RECT  6.421 2.529 6.467 4.576 ;
     RECT  6.323 7.929 6.805 8.601 ;
     RECT  2.052 13.329 6.805 14.432 ;
     RECT  3.397 10.88 7.475 10.912 ;
     RECT  6.805 13.184 7.571 14.432 ;
     RECT  6.805 6.784 8.291 8.601 ;
     RECT  7.571 13.184 8.677 14.001 ;
     RECT  8.677 12.16 10.307 14.001 ;
     RECT  8.291 7.929 10.693 8.601 ;
     RECT  8.533 9.984 10.693 10.016 ;
     RECT  6.467 2.529 11.173 4.128 ;
     RECT  10.693 7.929 11.173 10.016 ;
     RECT  11.173 6.784 11.507 10.016 ;
     RECT  11.173 2.529 11.941 4.32 ;
     RECT  11.507 6.784 12.035 8.601 ;
     RECT  11.507 9.984 12.035 10.016 ;
     RECT  10.307 13.184 12.563 14.001 ;
     RECT  11.941 2.304 12.611 4.32 ;
     RECT  12.611 2.529 12.659 4.32 ;
     RECT  12.659 2.529 15.174 3.201 ;
     RECT  12.035 7.929 15.174 8.601 ;
     RECT  12.563 13.329 15.174 14.001 ;
  END
END ot_s81_head_delay8x32
END LIBRARY
